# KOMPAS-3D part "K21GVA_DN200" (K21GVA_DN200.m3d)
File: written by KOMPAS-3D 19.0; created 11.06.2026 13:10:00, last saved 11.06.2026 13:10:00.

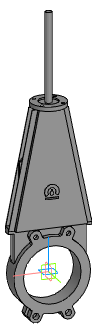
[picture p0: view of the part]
Document properties: Автор: Энергия; Полное имя файла: Z:\3.Личные\kachalov\001_3d для проектировщиков\2.5 Тип_K21GVA. Задвижка\_stp\_stp_K21GVA_DN50-DN1000_с фланцем\K21GVA_DN200.m3d

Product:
- Part/product: K21GVA_DN200

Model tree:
1. Операция без истории:1  (labels: K21GVA_DN200)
